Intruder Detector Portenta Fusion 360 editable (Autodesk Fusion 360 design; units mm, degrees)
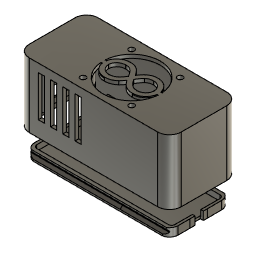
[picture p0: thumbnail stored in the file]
named bodies: "Cap", "Box (1)"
